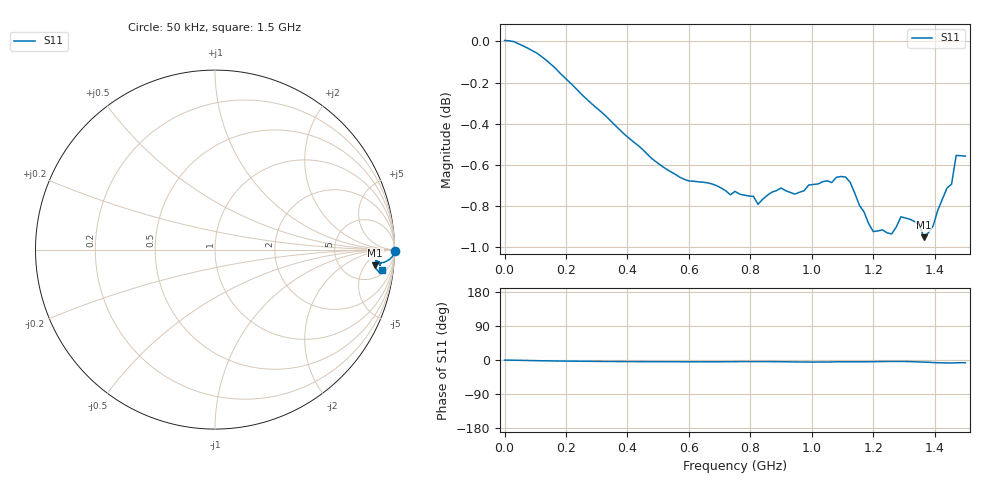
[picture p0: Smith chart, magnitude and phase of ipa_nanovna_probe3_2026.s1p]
! Touchstone S1P file exported from NanoVNA UTN Toolkit
! Device: NanoVNA-H
! Export date: 2026-10-13 12:28:27
! Frequency range: 0.050 - 1500.000 MHz
! Number of points: 101
! Parameter: S11 (Reflection)
# Hz S RI R 50
! f[Hz]  S11_real S11_imag
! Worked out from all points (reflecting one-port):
!   101 points, 50 kHz to 1.5 GHz, reference 50 ohm
!   lowest |S11| = -1.0 dB at 1.365 GHz (marker M1), VSWR 18.27, Z = 509 - j453 ohm
!   phase of S11 starts at -0 deg and turns -7 deg over the sweep
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50000  1 -0.00634
3.0049e7  0.9998 -0.00981
1.050465e8  0.993 -0.0306
1.950435e8  0.9788 -0.0488
3.750375e8  0.9493 -0.0674
5.70031e8  0.9239 -0.0741
6.450285e8  0.921 -0.077
7.50025e8  0.9168 -0.0704
8.10023e8  0.9145 -0.0668
8.250225e8  0.9104 -0.0666
8.550215e8  0.9149 -0.0677
9.0002e8  0.9183 -0.0729
9.450185e8  0.9145 -0.0806
1.005016e9  0.9188 -0.0885
1.110013e9  0.9238 -0.075
1.140012e9  0.9155 -0.0745
1.20001e9  0.8964 -0.0689
1.260008e9  0.8959 -0.0587
1.290007e9  0.9044 -0.062
1.320006e9  0.9027 -0.067
1.350005e9  0.8986 -0.0818
1.365004e9  0.892 -0.0874
1.380004e9  0.8936 -0.0934
1.395004e9  0.8957 -0.1056
1.440002e9  0.9128 -0.1235
1.455002e9  0.9145 -0.1265
1.470001e9  0.9303 -0.1208
1.5e9  0.9307 -0.1153
